VERSION 5.8 ;
UNITS
  DATABASE MICRONS 1000 ;
END UNITS

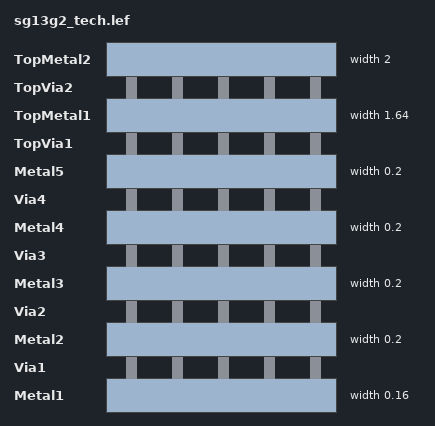
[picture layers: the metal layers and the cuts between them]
LAYER Metal1
  TYPE ROUTING ;   # routing layer
  WIDTH 0.16 ;
  WIDTH 0.5 0.6 ;
  RESISTANCE RPERSQ 0.1100 ;
  CAPACITANCE CPERSQDIST 3.500e-05 ;
  EDGECAPACITANCE 4.100e-05 ;
END Metal1

LAYER Via1
  TYPE CUT ;
  RESISTANCE 20.0 ;
END Via1

LAYER Metal2
  TYPE ROUTING ;   # routing layer
  WIDTH 0.2 ;
  WIDTH 0.5 0.6 ;
  RESISTANCE RPERSQ 0.0980 ;
  CAPACITANCE CPERSQDIST 3.200e-05 ;
  EDGECAPACITANCE 3.900e-05 ;
END Metal2

LAYER Via2
  TYPE CUT ;
  RESISTANCE 17.5 ;
END Via2

LAYER Metal3
  TYPE ROUTING ;   # routing layer
  WIDTH 0.2 ;
  WIDTH 0.5 0.6 ;
  RESISTANCE RPERSQ 0.0860 ;
  CAPACITANCE CPERSQDIST 2.900e-05 ;
  EDGECAPACITANCE 3.700e-05 ;
END Metal3

LAYER Via3
  TYPE CUT ;
  RESISTANCE 15.0 ;
END Via3

LAYER Metal4
  TYPE ROUTING ;   # routing layer
  WIDTH 0.2 ;
  WIDTH 0.5 0.6 ;
  RESISTANCE RPERSQ 0.0740 ;
  CAPACITANCE CPERSQDIST 2.600e-05 ;
  EDGECAPACITANCE 3.500e-05 ;
END Metal4

LAYER Via4
  TYPE CUT ;
  RESISTANCE 12.5 ;
END Via4

LAYER Metal5
  TYPE ROUTING ;   # routing layer
  WIDTH 0.2 ;
  WIDTH 0.5 0.6 ;
  RESISTANCE RPERSQ 0.0620 ;
  CAPACITANCE CPERSQDIST 2.300e-05 ;
  EDGECAPACITANCE 3.300e-05 ;
END Metal5

LAYER TopVia1
  TYPE CUT ;
  RESISTANCE 10.0 ;
END TopVia1

LAYER TopMetal1
  TYPE ROUTING ;   # routing layer
  WIDTH 1.64 ;
  WIDTH 0.5 0.6 ;
  RESISTANCE RPERSQ 0.0500 ;
  CAPACITANCE CPERSQDIST 2.000e-05 ;
  EDGECAPACITANCE 3.100e-05 ;
END TopMetal1

LAYER TopVia2
  TYPE CUT ;
  RESISTANCE 7.5 ;
END TopVia2

LAYER TopMetal2
  TYPE ROUTING ;   # routing layer
  WIDTH 2.0 ;
  WIDTH 0.5 0.6 ;
  RESISTANCE RPERSQ 0.0380 ;
  CAPACITANCE CPERSQDIST 1.700e-05 ;
  EDGECAPACITANCE 2.900e-05 ;
END TopMetal2
END LIBRARY
